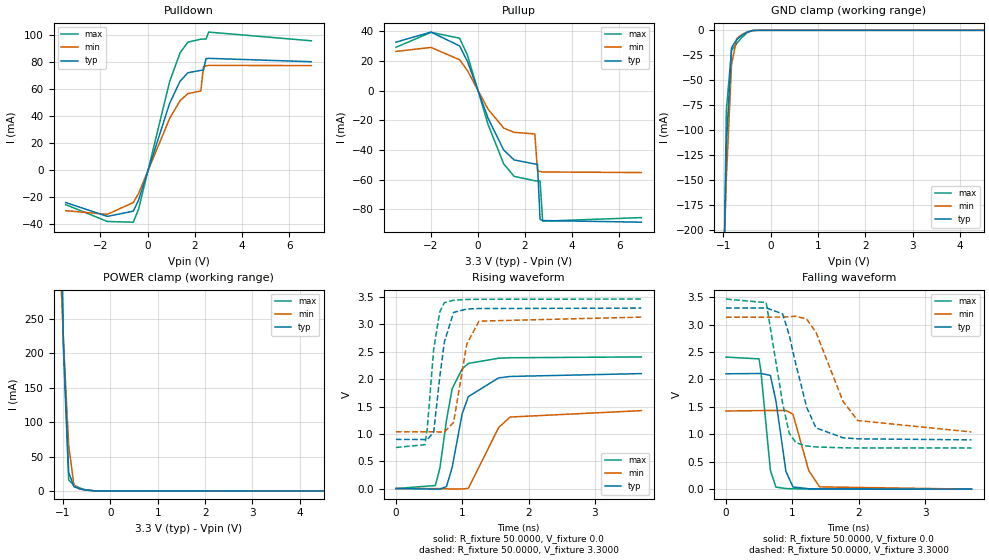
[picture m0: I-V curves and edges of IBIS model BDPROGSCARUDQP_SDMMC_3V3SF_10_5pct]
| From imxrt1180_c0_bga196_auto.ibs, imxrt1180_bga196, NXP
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[Model]  BDPROGSCARUDQP_SDMMC_3V3SF_10_5pct
|   Model BDPROGSCARUDQP_SDMMC_3V3SF_10_5pct
| This model was characterised for following simulation conditions:
| External (pad) voltage:
|   - Typ: 3.3V,   - Min: 3.135V,   - Max: 3.465V
| Library cells for typ/min/max conditions are connected as defined below:
|  IO - External Pad
|  A - Core Input
|  EN - Output Buffer Enable
|  ASRCN3V3[0] - REFH3V3
|  ASRCN3V3[1] - REFH3V3 REFH3V3 gnde
|  ASRCN3V3[2] - gnde
|  ASRCN3V3[3] - gnde REFH3V3 gnde
|  ASRCP3V3[0] - vdde3v3 REFL3V3 REFL3V3
|  ASRCP3V3[1] - vdde3v3 REFL3V3 vdde3v3
|  ASRCP3V3[2] - REFL3V3 vdde3v3 vdde3v3
|  ASRCP3V3[3] - REFL3V3 REFL3V3 vdde3v3
|  IOGC - NC
|  PDN - vdd
|  PDRV - gnd
|  PSW - vdd
|  PUN - vdd
|  REFH3V3 - REFH3V3
|  REFL3V3 - REFL3V3
|  ZI - NC
|  gnd - gnd
|  gnde - gnde
|  vdd - vdd
|  vdde3v3 - vdde3v3
| All other pins connected to ground
Model_type I/O
Polarity   Non-Inverting
Enable   Active-Low
Vinl =   0.7500V
Vinh =   2.2500V
Vmeas =  1.6500V
Cref =   30.0000pF
Rref =   1.0000M
Vref =   3.3000V
C_comp   2.0930pF   2.0588pF   2.1394pF
|C_comp_pullup   0.3784pF   0.3917pF   0.3680pF
|C_comp_pulldown   0.6261pF   0.6585pF   0.5996pF
[Model Spec]
| variable   typ   min   max
Vinh   2.0625V   1.9594V   2.1656V
Vinl   0.8250V   0.7837V   0.8662V
[Temperature Range]   25.0000   0.1250k   -40.0000
[Voltage Range]   3.3000V   3.1350V   3.4650V
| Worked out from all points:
|   slope of the pulldown table from 0 to 0.495 V, typ, clamps not added: 17.8 ohm
|   slope of the pullup table from 0 to 0.495 V, typ, clamps not added: 23.8 ohm
|   GND clamp passes 1 mA (typ) near -0.44 V on its own axis
|   POWER clamp passes 1 mA (typ) near -0.50 V on its own axis
|   rising waveform, R_fixture 50.0000, V_fixture 0.0: 20-80 % time 239ps typ, 300ps min, 197ps max; typ from 0 V to 2.1 V
|   rising waveform, R_fixture 50.0000, V_fixture 3.3000: 20-80 % time 145ps typ, 173ps min, 133ps max; typ from 0.899 V to 3.3 V
|   falling waveform, R_fixture 50.0000, V_fixture 0.0: 20-80 % time 145ps typ, 190ps min, 112ps max; typ from 2.1 V to 0 V
|   falling waveform, R_fixture 50.0000, V_fixture 3.3000: 20-80 % time 298ps typ, 419ps min, 205ps max; typ from 3.3 V to 0.898 V
[Pulldown]
|Voltage   I(typ)   I(min)   I(max)
-3.465V   -23.98mA   -30mA      -25.53mA
-1.705V   -34.25mA   -32.72mA   -38mA
-605mV    -30.33mA   -23.95mA   -38.53mA
-385mV    -22.24mA   -17.29mA   -29mA
935mV     49.66mA    38.46mA    65.78mA
1.375V    66.01mA    51.56mA    87.01mA
1.705V    72.25mA    56.77mA    94.93mA
2.255V    74.04mA    58.75mA    97.14mA
2.365V    74.11mA    76.66mA    97.2mA
2.475V    82.72mA    77.27mA    97.24mA
2.585V    82.93mA    77.74mA    102.4mA
6.93V     80.43mA    77.54mA    95.96mA
[Pullup]
|Voltage   I(typ)   I(min)   I(max)
-3.465V   32.75mA    26.5mA     29.27mA
-1.98V    39.56mA    29.21mA    39.39mA
-770mV    30.26mA    20.91mA    35.44mA
-440mV    19.92mA    13.71mA    24.2mA
440mV     -18.65mA   -12.54mA   -22.89mA
1.1V      -40.01mA   -25.21mA   -49.38mA
1.54V     -46.72mA   -28.09mA   -57.79mA
2.42V     -49.48mA   -29.2mA    -60.79mA
2.53V     -49.59mA   -54.16mA   -60.89mA
2.64V     -86.82mA   -54.55mA   -60.99mA
2.75V     -87.61mA   -54.84mA   -88.06mA
6.93V     -88.73mA   -55.23mA   -85.63mA
[GND_clamp]
|Voltage   I(typ)   I(min)   I(max)
-3.465V   -6.61A     -3.625A    -11.02A
-1.045V   -379.3mA   -320.9mA   -439.5mA
-935mV    -115.6mA   -149.2mA   -80.36mA
-825mV    -17.39mA   -34.03mA   -20.04mA
-715mV    -9.283mA   -8.196mA   -13.09mA
-605mV    -4.963mA   -4.061mA   -7.102mA
-495mV    -1.742mA   -1.709mA   -2.392mA
-385mV    -190.8uA   -374.3uA   -174uA
-275mV    -4.391uA   -28.37uA   -1.38uA
6.93V     0A         0A         0A
[POWER_clamp]
|Voltage   I(typ)   I(min)   I(max)
-3.465V   6.781A     3.709A     11.35A
-1.1V     518.6mA    402.6mA    656.4mA
-990mV    215.3mA    216.5mA    203.9mA
-880mV    27.02mA    66.67mA    15.93mA
-770mV    6.184mA    8.45mA     8.32mA
-660mV    3.401mA    3.057mA    4.697mA
-550mV    1.523mA    1.506mA    2.035mA
-330mV    50.46uA    136.8uA    38uA
6.93V     0A         0A         0A
[Ramp]
| variable   typ   min   max
dV/dt_r  1.2610/0.2391n   0.8547/0.2996n   1.4441/0.1966n
dV/dt_f  1.4409/0.2978n   1.2561/0.4190n   1.6286/0.2054n
R_load = 50.0000
[Rising Waveform]
R_fixture= 50.0000
V_fixture= 0.0
V_fixture_min= 0.0
V_fixture_max= 0.0
|time   V(typ)   V(min)   V(max)
0s        27nV       808.8nV    40.5nV
594.3ps   -11.11mV   -87.89uV   55.42mV
663.1ps   -10.13mV   -1.591mV   374.3mV
762.5ps   36.58mV    -4.5mV     1.251V
848.1ps   389.8mV    -8.621mV   1.827V
999ps     1.369V     -7.86mV    2.189V
1.092ns   1.681V     5.716mV    2.288V
1.547ns   2.023V     1.113V     2.383V
1.722ns   2.05V      1.308V     2.392V
3.7ns     2.102V     1.425V     2.407V
[Rising Waveform]
R_fixture= 50.0000
V_fixture= 3.3000
V_fixture_min= 3.1350
V_fixture_max= 3.4650
|time   V(typ)   V(min)   V(max)
0s        899mV      1.037V     751.1mV
437.3ps   897.2mV    1.037V     802.4mV
472ps     893.7mV    1.037V     1.091V
570ps     1.034V     1.037V     2.558V
661.7ps   2.05V      1.035V     3.233V
730.8ps   2.682V     1.033V     3.4V
869ps     3.221V     1.21V      3.443V
1.069ns   3.283V     2.645V     3.458V
1.252ns   3.292V     3.062V     3.461V
3.7ns     3.3V       3.135V     3.465V
[Falling Waveform]
R_fixture= 50.0000
V_fixture= 0.0
V_fixture_min= 0.0
V_fixture_max= 0.0
|time   V(typ)   V(min)   V(max)
0s        2.103V     1.425V     2.407V
497ps     2.108V     1.432V     2.375V
524.9ps   2.109V     1.432V     2.158V
668.6ps   2.073V     1.434V     343.2mV
751.8ps   1.609V     1.434V     37.83mV
903.5ps   321.2mV    1.435V     11.04mV
1.009ns   40.3mV     1.366V     6.87mV
1.247ns   7.74mV     337.6mV    3.023mV
1.411ns   4.65mV     41.78mV    1.841mV
3.7ns     78.91uV    190.1uV    42uV
[Falling Waveform]
R_fixture= 50.0000
V_fixture= 3.3000
V_fixture_min= 3.1350
V_fixture_max= 3.4650
|time   V(typ)   V(min)   V(max)
0s        3.3V       3.135V     3.465V
605.7ps   3.304V     3.135V     3.4V
853ps     3.195V     3.136V     1.568V
952.1ps   2.808V     3.143V     1.023V
1.052ns   2.278V     3.153V     846.6mV
1.216ns   1.49V      3.099V     787.1mV
1.356ns   1.117V     2.859V     769.7mV
1.763ns   936.5mV    1.602V     753.7mV
1.985ns   917.3mV    1.251V     751.4mV
3.7ns     898.4mV    1.042V     750.7mV
